VERSION 5.7 ;
  NOWIREEXTENSIONATPIN ON ;
  DIVIDERCHAR "/" ;
  BUSBITCHARS "[]" ;
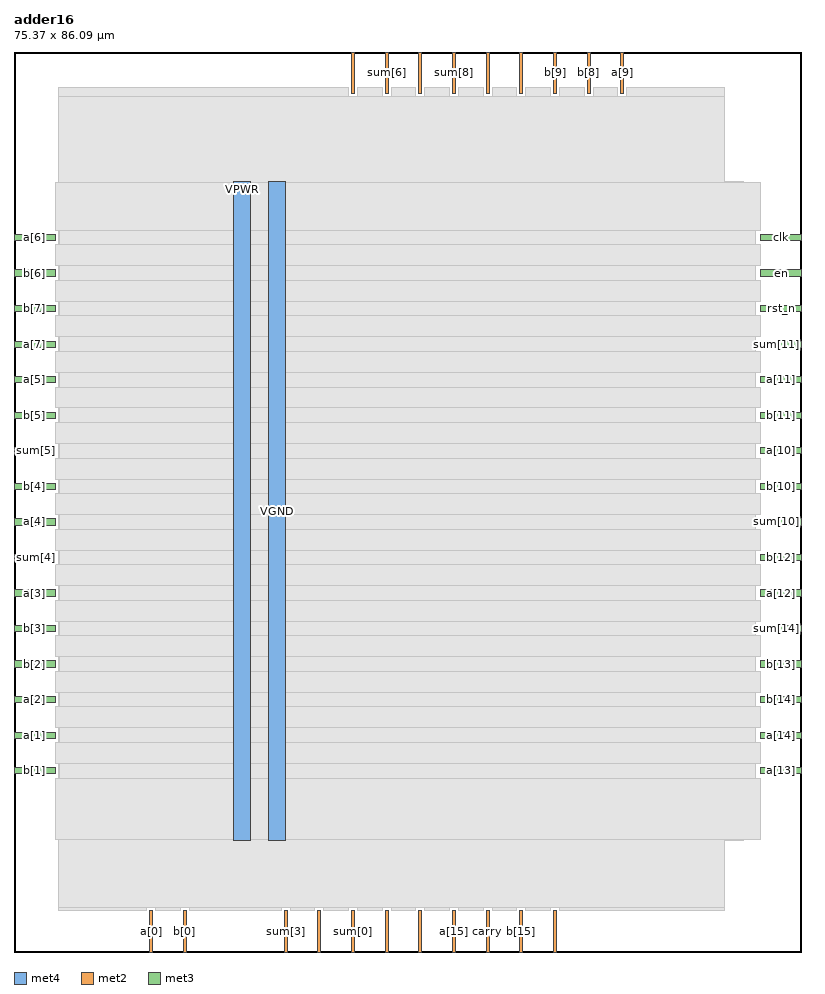
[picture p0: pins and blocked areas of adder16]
MACRO adder16
  CLASS BLOCK ;
  FOREIGN adder16 ;
  ORIGIN 0.000 0.000 ;
  SIZE 75.370 BY 86.090 ;
  PIN VGND
    DIRECTION INOUT ;
    USE GROUND ;
    PORT
      LAYER met4 ;
        RECT 24.340 10.640 25.940 73.680 ;
    END
  END VGND
  PIN VPWR
    DIRECTION INOUT ;
    USE POWER ;
    PORT
      LAYER met4 ;
        RECT 21.040 10.640 22.640 73.680 ;
    END
  END VPWR
  PIN a[0]
    DIRECTION INPUT ;
    USE SIGNAL ;
    ANTENNAGATEAREA 0.159000 ;
    PORT
      LAYER met2 ;
        RECT 12.970 0.000 13.250 4.000 ;
    END
  END a[0]
  PIN a[10]
    DIRECTION INPUT ;
    USE SIGNAL ;
    ANTENNAGATEAREA 0.196500 ;
    PORT
      LAYER met3 ;
        RECT 71.370 47.640 75.370 48.240 ;
    END
  END a[10]
  PIN a[11]
    DIRECTION INPUT ;
    USE SIGNAL ;
    ANTENNAGATEAREA 0.196500 ;
    PORT
      LAYER met3 ;
        RECT 71.370 54.440 75.370 55.040 ;
    END
  END a[11]
  PIN a[12]
    DIRECTION INPUT ;
    USE SIGNAL ;
    ANTENNAGATEAREA 0.196500 ;
    PORT
      LAYER met3 ;
        RECT 71.370 34.040 75.370 34.640 ;
    END
  END a[12]
  PIN a[13]
    DIRECTION INPUT ;
    USE SIGNAL ;
    ANTENNAGATEAREA 0.126000 ;
    PORT
      LAYER met3 ;
        RECT 71.370 17.040 75.370 17.640 ;
    END
  END a[13]
  PIN a[14]
    DIRECTION INPUT ;
    USE SIGNAL ;
    ANTENNAGATEAREA 0.196500 ;
    PORT
      LAYER met3 ;
        RECT 71.370 20.440 75.370 21.040 ;
    END
  END a[14]
  PIN a[15]
    DIRECTION INPUT ;
    USE SIGNAL ;
    ANTENNAGATEAREA 0.196500 ;
    PORT
      LAYER met2 ;
        RECT 41.950 0.000 42.230 4.000 ;
    END
  END a[15]
  PIN a[1]
    DIRECTION INPUT ;
    USE SIGNAL ;
    ANTENNAGATEAREA 0.247500 ;
    PORT
      LAYER met3 ;
        RECT 0.000 20.440 4.000 21.040 ;
    END
  END a[1]
  PIN a[2]
    DIRECTION INPUT ;
    USE SIGNAL ;
    ANTENNAGATEAREA 0.196500 ;
    PORT
      LAYER met3 ;
        RECT 0.000 23.840 4.000 24.440 ;
    END
  END a[2]
  PIN a[3]
    DIRECTION INPUT ;
    USE SIGNAL ;
    ANTENNAGATEAREA 0.196500 ;
    PORT
      LAYER met3 ;
        RECT 0.000 34.040 4.000 34.640 ;
    END
  END a[3]
  PIN a[4]
    DIRECTION INPUT ;
    USE SIGNAL ;
    ANTENNAGATEAREA 0.196500 ;
    PORT
      LAYER met3 ;
        RECT 0.000 40.840 4.000 41.440 ;
    END
  END a[4]
  PIN a[5]
    DIRECTION INPUT ;
    USE SIGNAL ;
    ANTENNAGATEAREA 0.196500 ;
    PORT
      LAYER met3 ;
        RECT 0.000 54.440 4.000 55.040 ;
    END
  END a[5]
  PIN a[6]
    DIRECTION INPUT ;
    USE SIGNAL ;
    ANTENNAGATEAREA 0.196500 ;
    PORT
      LAYER met3 ;
        RECT 0.000 68.040 4.000 68.640 ;
    END
  END a[6]
  PIN a[7]
    DIRECTION INPUT ;
    USE SIGNAL ;
    ANTENNAGATEAREA 0.196500 ;
    PORT
      LAYER met3 ;
        RECT 0.000 57.840 4.000 58.440 ;
    END
  END a[7]
  PIN a[8]
    DIRECTION INPUT ;
    USE SIGNAL ;
    ANTENNAGATEAREA 0.196500 ;
    PORT
      LAYER met2 ;
        RECT 45.170 82.090 45.450 86.090 ;
    END
  END a[8]
  PIN a[9]
    DIRECTION INPUT ;
    USE SIGNAL ;
    ANTENNAGATEAREA 0.126000 ;
    PORT
      LAYER met2 ;
        RECT 58.050 82.090 58.330 86.090 ;
    END
  END a[9]
  PIN b[0]
    DIRECTION INPUT ;
    USE SIGNAL ;
    ANTENNAGATEAREA 0.159000 ;
    PORT
      LAYER met2 ;
        RECT 16.190 0.000 16.470 4.000 ;
    END
  END b[0]
  PIN b[10]
    DIRECTION INPUT ;
    USE SIGNAL ;
    ANTENNAGATEAREA 0.196500 ;
    PORT
      LAYER met3 ;
        RECT 71.370 44.240 75.370 44.840 ;
    END
  END b[10]
  PIN b[11]
    DIRECTION INPUT ;
    USE SIGNAL ;
    ANTENNAGATEAREA 0.196500 ;
    PORT
      LAYER met3 ;
        RECT 71.370 51.040 75.370 51.640 ;
    END
  END b[11]
  PIN b[12]
    DIRECTION INPUT ;
    USE SIGNAL ;
    ANTENNAGATEAREA 0.196500 ;
    PORT
      LAYER met3 ;
        RECT 71.370 37.440 75.370 38.040 ;
    END
  END b[12]
  PIN b[13]
    DIRECTION INPUT ;
    USE SIGNAL ;
    ANTENNAGATEAREA 0.196500 ;
    PORT
      LAYER met3 ;
        RECT 71.370 27.240 75.370 27.840 ;
    END
  END b[13]
  PIN b[14]
    DIRECTION INPUT ;
    USE SIGNAL ;
    ANTENNAGATEAREA 0.196500 ;
    PORT
      LAYER met3 ;
        RECT 71.370 23.840 75.370 24.440 ;
    END
  END b[14]
  PIN b[15]
    DIRECTION INPUT ;
    USE SIGNAL ;
    ANTENNAGATEAREA 0.196500 ;
    PORT
      LAYER met2 ;
        RECT 48.390 0.000 48.670 4.000 ;
    END
  END b[15]
  PIN b[1]
    DIRECTION INPUT ;
    USE SIGNAL ;
    ANTENNAGATEAREA 0.247500 ;
    PORT
      LAYER met3 ;
        RECT 0.000 17.040 4.000 17.640 ;
    END
  END b[1]
  PIN b[2]
    DIRECTION INPUT ;
    USE SIGNAL ;
    ANTENNAGATEAREA 0.196500 ;
    PORT
      LAYER met3 ;
        RECT 0.000 27.240 4.000 27.840 ;
    END
  END b[2]
  PIN b[3]
    DIRECTION INPUT ;
    USE SIGNAL ;
    ANTENNAGATEAREA 0.196500 ;
    PORT
      LAYER met3 ;
        RECT 0.000 30.640 4.000 31.240 ;
    END
  END b[3]
  PIN b[4]
    DIRECTION INPUT ;
    USE SIGNAL ;
    ANTENNAGATEAREA 0.196500 ;
    PORT
      LAYER met3 ;
        RECT 0.000 44.240 4.000 44.840 ;
    END
  END b[4]
  PIN b[5]
    DIRECTION INPUT ;
    USE SIGNAL ;
    ANTENNAGATEAREA 0.196500 ;
    PORT
      LAYER met3 ;
        RECT 0.000 51.040 4.000 51.640 ;
    END
  END b[5]
  PIN b[6]
    DIRECTION INPUT ;
    USE SIGNAL ;
    ANTENNAGATEAREA 0.196500 ;
    PORT
      LAYER met3 ;
        RECT 0.000 64.640 4.000 65.240 ;
    END
  END b[6]
  PIN b[7]
    DIRECTION INPUT ;
    USE SIGNAL ;
    ANTENNAGATEAREA 0.196500 ;
    PORT
      LAYER met3 ;
        RECT 0.000 61.240 4.000 61.840 ;
    END
  END b[7]
  PIN b[8]
    DIRECTION INPUT ;
    USE SIGNAL ;
    ANTENNAGATEAREA 0.196500 ;
    PORT
      LAYER met2 ;
        RECT 54.830 82.090 55.110 86.090 ;
    END
  END b[8]
  PIN b[9]
    DIRECTION INPUT ;
    USE SIGNAL ;
    ANTENNAGATEAREA 0.196500 ;
    PORT
      LAYER met2 ;
        RECT 51.610 82.090 51.890 86.090 ;
    END
  END b[9]
  PIN carry
    DIRECTION OUTPUT ;
    USE SIGNAL ;
    ANTENNADIFFAREA 0.340600 ;
    PORT
      LAYER met2 ;
        RECT 45.170 0.000 45.450 4.000 ;
    END
  END carry
  PIN clk
    DIRECTION INPUT ;
    USE SIGNAL ;
    ANTENNAGATEAREA 0.852000 ;
    PORT
      LAYER met3 ;
        RECT 71.370 68.040 75.370 68.640 ;
    END
  END clk
  PIN en
    DIRECTION INPUT ;
    USE SIGNAL ;
    ANTENNAGATEAREA 0.247500 ;
    PORT
      LAYER met3 ;
        RECT 71.370 64.640 75.370 65.240 ;
    END
  END en
  PIN rst_n
    DIRECTION INPUT ;
    USE SIGNAL ;
    ANTENNAGATEAREA 0.426000 ;
    PORT
      LAYER met3 ;
        RECT 71.370 61.240 75.370 61.840 ;
    END
  END rst_n
  PIN sum[0]
    DIRECTION OUTPUT ;
    USE SIGNAL ;
    ANTENNADIFFAREA 0.340600 ;
    PORT
      LAYER met2 ;
        RECT 32.290 0.000 32.570 4.000 ;
    END
  END sum[0]
  PIN sum[10]
    DIRECTION OUTPUT ;
    USE SIGNAL ;
    ANTENNADIFFAREA 0.340600 ;
    PORT
      LAYER met3 ;
        RECT 71.370 40.840 75.370 41.440 ;
    END
  END sum[10]
  PIN sum[11]
    DIRECTION OUTPUT ;
    USE SIGNAL ;
    ANTENNADIFFAREA 0.340600 ;
    PORT
      LAYER met3 ;
        RECT 71.370 57.840 75.370 58.440 ;
    END
  END sum[11]
  PIN sum[12]
    DIRECTION OUTPUT ;
    USE SIGNAL ;
    ANTENNADIFFAREA 0.340600 ;
    PORT
      LAYER met2 ;
        RECT 38.730 82.090 39.010 86.090 ;
    END
  END sum[12]
  PIN sum[13]
    DIRECTION OUTPUT ;
    USE SIGNAL ;
    ANTENNADIFFAREA 0.340600 ;
    PORT
      LAYER met2 ;
        RECT 38.730 0.000 39.010 4.000 ;
    END
  END sum[13]
  PIN sum[14]
    DIRECTION OUTPUT ;
    USE SIGNAL ;
    ANTENNADIFFAREA 0.340600 ;
    PORT
      LAYER met3 ;
        RECT 71.370 30.640 75.370 31.240 ;
    END
  END sum[14]
  PIN sum[15]
    DIRECTION OUTPUT ;
    USE SIGNAL ;
    ANTENNADIFFAREA 0.340600 ;
    PORT
      LAYER met2 ;
        RECT 51.610 0.000 51.890 4.000 ;
    END
  END sum[15]
  PIN sum[1]
    DIRECTION OUTPUT ;
    USE SIGNAL ;
    ANTENNADIFFAREA 0.340600 ;
    PORT
      LAYER met2 ;
        RECT 29.070 0.000 29.350 4.000 ;
    END
  END sum[1]
  PIN sum[2]
    DIRECTION OUTPUT ;
    USE SIGNAL ;
    ANTENNADIFFAREA 0.340600 ;
    PORT
      LAYER met2 ;
        RECT 35.510 0.000 35.790 4.000 ;
    END
  END sum[2]
  PIN sum[3]
    DIRECTION OUTPUT ;
    USE SIGNAL ;
    ANTENNADIFFAREA 0.340600 ;
    PORT
      LAYER met2 ;
        RECT 25.850 0.000 26.130 4.000 ;
    END
  END sum[3]
  PIN sum[4]
    DIRECTION OUTPUT ;
    USE SIGNAL ;
    ANTENNADIFFAREA 0.340600 ;
    PORT
      LAYER met3 ;
        RECT 0.000 37.440 4.000 38.040 ;
    END
  END sum[4]
  PIN sum[5]
    DIRECTION OUTPUT ;
    USE SIGNAL ;
    ANTENNADIFFAREA 0.340600 ;
    PORT
      LAYER met3 ;
        RECT 0.000 47.640 4.000 48.240 ;
    END
  END sum[5]
  PIN sum[6]
    DIRECTION OUTPUT ;
    USE SIGNAL ;
    ANTENNADIFFAREA 0.340600 ;
    PORT
      LAYER met2 ;
        RECT 35.510 82.090 35.790 86.090 ;
    END
  END sum[6]
  PIN sum[7]
    DIRECTION OUTPUT ;
    USE SIGNAL ;
    ANTENNADIFFAREA 0.340600 ;
    PORT
      LAYER met2 ;
        RECT 32.290 82.090 32.570 86.090 ;
    END
  END sum[7]
  PIN sum[8]
    DIRECTION OUTPUT ;
    USE SIGNAL ;
    ANTENNADIFFAREA 0.340600 ;
    PORT
      LAYER met2 ;
        RECT 41.950 82.090 42.230 86.090 ;
    END
  END sum[8]
  PIN sum[9]
    DIRECTION OUTPUT ;
    USE SIGNAL ;
    ANTENNADIFFAREA 0.340600 ;
    PORT
      LAYER met2 ;
        RECT 48.390 82.090 48.670 86.090 ;
    END
  END sum[9]
  OBS
      LAYER nwell ;
        RECT 5.330 10.795 69.650 73.630 ;
      LAYER li1 ;
        RECT 5.520 10.795 69.460 73.525 ;
      LAYER met1 ;
        RECT 4.210 10.640 69.760 73.680 ;
      LAYER met2 ;
        RECT 4.230 81.810 32.010 82.690 ;
        RECT 32.850 81.810 35.230 82.690 ;
        RECT 36.070 81.810 38.450 82.690 ;
        RECT 39.290 81.810 41.670 82.690 ;
        RECT 42.510 81.810 44.890 82.690 ;
        RECT 45.730 81.810 48.110 82.690 ;
        RECT 48.950 81.810 51.330 82.690 ;
        RECT 52.170 81.810 54.550 82.690 ;
        RECT 55.390 81.810 57.770 82.690 ;
        RECT 58.610 81.810 67.990 82.690 ;
        RECT 4.230 4.280 67.990 81.810 ;
        RECT 4.230 4.000 12.690 4.280 ;
        RECT 13.530 4.000 15.910 4.280 ;
        RECT 16.750 4.000 25.570 4.280 ;
        RECT 26.410 4.000 28.790 4.280 ;
        RECT 29.630 4.000 32.010 4.280 ;
        RECT 32.850 4.000 35.230 4.280 ;
        RECT 36.070 4.000 38.450 4.280 ;
        RECT 39.290 4.000 41.670 4.280 ;
        RECT 42.510 4.000 44.890 4.280 ;
        RECT 45.730 4.000 48.110 4.280 ;
        RECT 48.950 4.000 51.330 4.280 ;
        RECT 52.170 4.000 67.990 4.280 ;
      LAYER met3 ;
        RECT 3.990 69.040 71.370 73.605 ;
        RECT 4.400 67.640 70.970 69.040 ;
        RECT 3.990 65.640 71.370 67.640 ;
        RECT 4.400 64.240 70.970 65.640 ;
        RECT 3.990 62.240 71.370 64.240 ;
        RECT 4.400 60.840 70.970 62.240 ;
        RECT 3.990 58.840 71.370 60.840 ;
        RECT 4.400 57.440 70.970 58.840 ;
        RECT 3.990 55.440 71.370 57.440 ;
        RECT 4.400 54.040 70.970 55.440 ;
        RECT 3.990 52.040 71.370 54.040 ;
        RECT 4.400 50.640 70.970 52.040 ;
        RECT 3.990 48.640 71.370 50.640 ;
        RECT 4.400 47.240 70.970 48.640 ;
        RECT 3.990 45.240 71.370 47.240 ;
        RECT 4.400 43.840 70.970 45.240 ;
        RECT 3.990 41.840 71.370 43.840 ;
        RECT 4.400 40.440 70.970 41.840 ;
        RECT 3.990 38.440 71.370 40.440 ;
        RECT 4.400 37.040 70.970 38.440 ;
        RECT 3.990 35.040 71.370 37.040 ;
        RECT 4.400 33.640 70.970 35.040 ;
        RECT 3.990 31.640 71.370 33.640 ;
        RECT 4.400 30.240 70.970 31.640 ;
        RECT 3.990 28.240 71.370 30.240 ;
        RECT 4.400 26.840 70.970 28.240 ;
        RECT 3.990 24.840 71.370 26.840 ;
        RECT 4.400 23.440 70.970 24.840 ;
        RECT 3.990 21.440 71.370 23.440 ;
        RECT 4.400 20.040 70.970 21.440 ;
        RECT 3.990 18.040 71.370 20.040 ;
        RECT 4.400 16.640 70.970 18.040 ;
        RECT 3.990 10.715 71.370 16.640 ;
  END
END adder16
END LIBRARY

